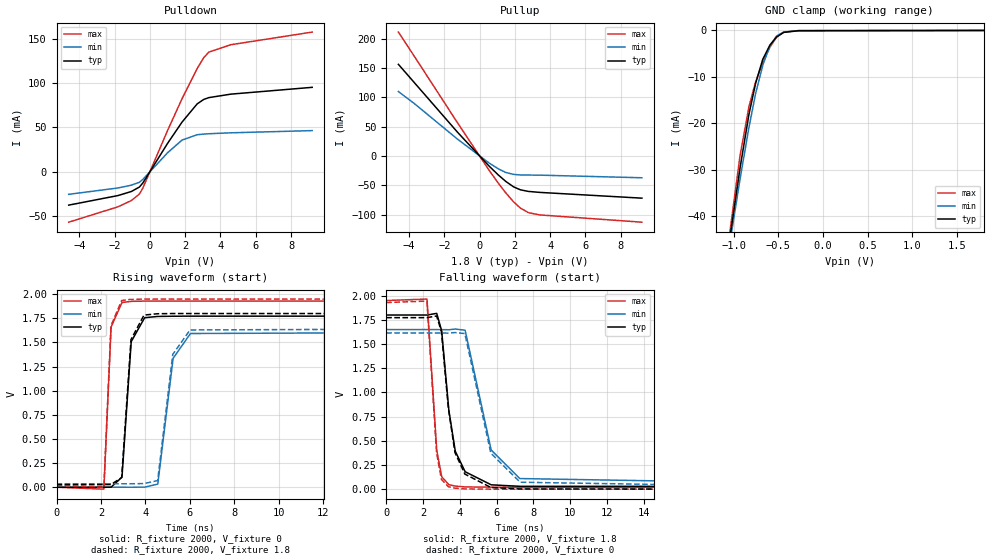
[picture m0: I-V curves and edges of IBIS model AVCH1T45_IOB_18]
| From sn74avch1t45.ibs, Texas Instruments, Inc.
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[Model]   AVCH1T45_IOB_18
Model_type  I/O
Vinl=0.5775
Vinh=1.2675
Enable   Active-High
Vref =   0
Rref =   2000
Cref =   15p
Vmeas =   0.9
| variable   typ   min   max
C_comp   5.26pF   4.50pF   5.87pF
| C_pullup   4.78pF   3.53pF   6.89pF
| C_pulldown   4.68pF   4.09pF   5.05pF
| C_tri-state   5.26pF   4.50pF   5.87pF
[Temperature Range]   40   100   -40
| Ambient temperature   25   85   -40
[Voltage range]   1.8   1.65   1.95
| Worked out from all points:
|   slope of the pulldown table from 0 to 0.27 V, typ, clamps not added: 30.8 ohm
|   slope of the pullup table from 0 to 0.27 V, typ, clamps not added: 31.4 ohm
|   GND clamp passes 1 mA (typ) near -0.49 V on its own axis
|   rising waveform, R_fixture 2000, V_fixture 0: 20-80 % time 290ps typ, 449ps min, 186ps max; typ from 0 V to 1.77 V
|   falling waveform, R_fixture 2000, V_fixture 1.8: 20-80 % time 652ps typ, 999ps min, 373ps max; typ from 1.8 V to 0.027 V
|   rising waveform, R_fixture 2000, V_fixture 1.8: 20-80 % time 288ps typ, 441ps min, 184ps max; typ from 0.027 V to 1.8 V
|   falling waveform, R_fixture 2000, V_fixture 0: 20-80 % time 653ps typ, 998ps min, 361ps max; typ from 1.77 V to 0 V
[GND Clamp]
| AVCH1T45_IOB_18
|   Voltage   I(typ)   I(min)   I(max)
-4.6V     -599.6mA   -548.2mA   -664.6mA
-1.1V     -52.38mA   -52.81mA   -51.88mA
-1.075V   -48.92mA   -49.68mA   -47.98mA
-930mV    -29.69mA   -32.08mA   -27.04mA
-830mV    -18.1mA    -20.91mA   -16.44mA
-755mV    -11.37mA   -13.59mA   -11.08mA
-675mV    -6.227mA   -7.502mA   -6.966mA
-595mV    -3.153mA   -3.319mA   -3.603mA
-520mV    -1.409mA   -1.191mA   -1.426mA
-440mV    -417.5uA   -333.3uA   -376.2uA
-275mV    -54.37uA   -36.84uA   -89.06uA
1.8V      918.7pA    21.47uA    -48.34uA
[Pulldown]
| AVCH1T45_IOB_18
|   Voltage   I(typ)   I(min)   I(max)
-4.6V     -37.94mA   -25.73mA   -57.23mA
-1.8V     -27.09mA   -18.52mA   -39.79mA
-1.045V   -22.5mA    -15.36mA   -32.7mA
-590mV    -17.44mA   -12.06mA   -25.35mA
-395mV    -12.81mA   -8.801mA   -18.52mA
1.005V    31.93mA    21.31mA    46.48mA
1.825V    55.97mA    35.61mA    82.46mA
2.68V     76.51mA    41.68mA    116.5mA
3.05V     81.53mA    42.39mA    128.7mA
3.34V     83.6mA     42.77mA    135mA
4.585V    87.54mA    43.82mA    143.4mA
9.2V      95.24mA    46.32mA    157.7mA
[Pullup]
| AVCH1T45_IOB_18
|   Voltage   I(typ)   I(min)   I(max)
-4.6V     156.3mA    109.9mA    211.2mA
-3.695V   125.1mA    89.45mA    169.9mA
-1.245V   40.55mA    28.8mA     56.51mA
535mV     -16.77mA   -11.6mA    -23.84mA
1.065V    -32.16mA   -21.66mA   -46.14mA
1.49V     -43.16mA   -27.88mA   -62.67mA
1.925V    -52.28mA   -31.05mA   -77.72mA
2.305V    -57.27mA   -32.09mA   -88.3mA
2.77V     -60.1mA    -32.26mA   -96.25mA
3.4V      -61.74mA   -32.39mA   -100.1mA
9.2V      -71.58mA   -36.85mA   -112.5mA
[Ramp]
| AVCH1T45_IOB_18
| variable   typ   min   max
dV/dt_r   1.08/3.02E-10   0.99/4.61E-10   1.17/1.95E-10
dV/dt_f   1.07/6.57E-10   0.98/1.01E-09   1.17/3.78E-10
R_load = 2000
[Rising Waveform]
| AVCH1T45_IOB_18
R_fixture =   2000
C_fixture =   0
L_fixture =   0
V_fixture =   0
V_fixture_min = 0
V_fixture_max = 0
|   Time   V(typ)   V(min)   V(max)
0s        21.35nV    98.25nV    665.6pV
2.13ns    39.05uV    -110.4nV   -20.1mV
2.455ns   604.2uV    -20.5uV    1.66V
2.945ns   104.5mV    15.93uV    1.914V
3.36ns    1.509V     -172.9uV   1.926V
3.965ns   1.757V     999.3uV    1.929V
4.555ns   1.77V      32.27mV    1.929V
5.245ns   1.772V     1.336V     1.929V
6.025ns   1.773V     1.593V     1.929V
29.99ns   1.773V     1.615V     1.929V
[Falling Waveform]
| AVCH1T45_IOB_18
R_fixture =   2000
C_fixture =   0
L_fixture =   0
V_fixture =   1.8
V_fixture_min = 1.65
V_fixture_max = 1.95
|   Time   V(typ)   V(min)   V(max)
0s        1.8V       1.65V      1.95V
2.215ns   1.8V       1.65V      1.965V
2.745ns   1.817V     1.65V      405.1mV
3.015ns   1.636V     1.649V     129mV
3.405ns   814.9mV    1.648V     46.72mV
3.755ns   392.1mV    1.655V     32.04mV
4.29ns    180.1mV    1.643V     23.24mV
5.705ns   44.96mV    405.1mV    20.42mV
7.26ns    29.59mV    109.7mV    20.34mV
29.99ns   27.01mV    36.05mV    20.32mV
[Rising Waveform]
| AVCH1T45_IOB_18
R_fixture =   2000
C_fixture =   0
L_fixture =   0
V_fixture =   1.8
V_fixture_min = 1.65
V_fixture_max = 1.95
|   Time   V(typ)   V(min)   V(max)
0s        27.01mV    36.05mV    20.32mV
2.13ns    27.05mV    36.05mV    495uV
2.45ns    27.53mV    36.03mV    1.673V
2.93ns    100.5mV    36.07mV    1.935V
3.35ns    1.53V      35.88mV    1.947V
3.935ns   1.784V     37.89mV    1.95V
4.55ns    1.798V     68.99mV    1.95V
5.23ns    1.8V       1.377V     1.95V
6.005ns   1.8V       1.63V      1.95V
29.99ns   1.8V       1.65V      1.95V
[Falling Waveform]
| AVCH1T45_IOB_18
R_fixture =   2000
C_fixture =   0
L_fixture =   0
V_fixture =   0
V_fixture_min = 0
V_fixture_max = 0
|   Time   V(typ)   V(min)   V(max)
0s        1.773V     1.615V     1.929V
2.215ns   1.773V     1.615V     1.944V
2.74ns    1.79V      1.615V     371.5mV
3ns       1.629V     1.614V     102mV
3.375ns   842.1mV    1.613V     26.04mV
3.735ns   379.7mV    1.619V     10.93mV
4.275ns   156mV      1.608V     2.612mV
5.69ns    17.29mV    370.9mV    85.87uV
7.28ns    2.194mV    71.85mV    11.35uV
29.99ns   89.43nV    1.385uV    172.5nV
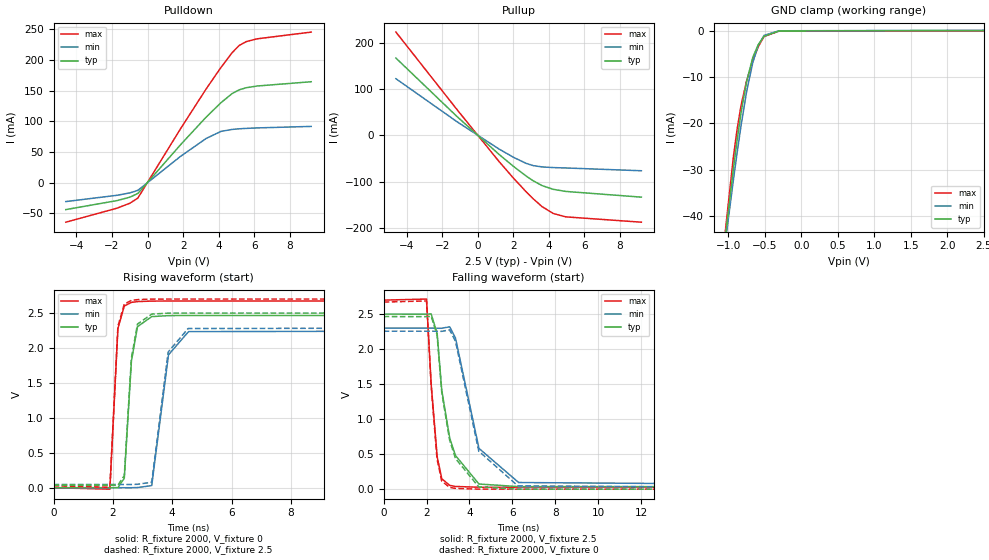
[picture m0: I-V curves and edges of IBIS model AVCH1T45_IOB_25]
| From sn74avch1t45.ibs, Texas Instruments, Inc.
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[Model]   AVCH1T45_IOB_25
Model_type  I/O
Vinl=0.7
Vinh=1.6
Enable   Active-High
Vref =   0
Rref =   2000
Cref =   15p
Vmeas =   1.25
| variable   typ   min   max
C_comp   5.06pF   4.25pF   5.75pF
| C_pullup   4.25pF   3.21pF   5.63pF
| C_pulldown   4.37pF   3.82pF   4.80pF
| C_tri-state   5.06pF   4.25pF   5.75pF
[Temperature Range]   40   100   -40
| Ambient temperature   25   85   -40
[Voltage range]   2.5   2.3   2.7
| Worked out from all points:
|   slope of the pulldown table from 0 to 0.375 V, typ, clamps not added: 29.4 ohm
|   slope of the pullup table from 0 to 0.375 V, typ, clamps not added: 28.8 ohm
|   GND clamp passes 1 mA (typ) near -0.49 V on its own axis
|   rising waveform, R_fixture 2000, V_fixture 0: 20-80 % time 216ps typ, 348ps min, 156ps max; typ from 0 V to 2.46 V
|   falling waveform, R_fixture 2000, V_fixture 2.5: 20-80 % time 733ps typ, 1.05ns min, 340ps max; typ from 2.5 V to 0.036 V
|   rising waveform, R_fixture 2000, V_fixture 2.5: 20-80 % time 214ps typ, 345ps min, 155ps max; typ from 0.036 V to 2.5 V
|   falling waveform, R_fixture 2000, V_fixture 0: 20-80 % time 728ps typ, 1.05ns min, 333ps max; typ from 2.46 V to 0 V
[GND Clamp]
| AVCH1T45_IOB_25
|   Voltage   I(typ)   I(min)   I(max)
-4.6V     -599.7mA   -548.2mA   -664.8mA
-1.105V   -53.1mA    -53.46mA   -52.72mA
-1.08V    -49.64mA   -50.32mA   -48.82mA
-930mV    -29.72mA   -32.1mA    -27.1mA
-880mV    -23.65mA   -26.37mA   -21.29mA
-825mV    -17.62mA   -20.4mA    -16.07mA
-750mV    -11.02mA   -13.17mA   -10.85mA
-665mV    -5.769mA   -6.898mA   -6.554mA
-590mV    -3.043mA   -3.142mA   -3.475mA
-510mV    -1.266mA   -1.045mA   -1.273mA
-305mV    -86.62uA   -60.85uA   -133.1uA
2.5V      1.212nA    39.39uA    -82.83uA
[Pulldown]
| AVCH1T45_IOB_25
|   Voltage   I(typ)   I(min)   I(max)
-4.6V     -43.76mA   -30.71mA   -64.27mA
-1.715V   -29.08mA   -20.46mA   -41.45mA
-985mV    -23.44mA   -16.53mA   -33.24mA
-545mV    -17.41mA   -12.35mA   -24.86mA
1.85V     61.76mA    42.85mA    87.78mA
3.295V    106.9mA    72.08mA    152.8mA
4.12V     130.1mA    83.49mA    187.5mA
4.755V    145.2mA    86.77mA    211.8mA
5.15V     151.2mA    87.75mA    223.4mA
5.545V    154.6mA    88.42mA    229.7mA
6.15V     157.4mA    89.19mA    234.2mA
9.2V      164.4mA    91.67mA    245.2mA
[Pullup]
| AVCH1T45_IOB_25
|   Voltage   I(typ)   I(min)   I(max)
-4.6V     167.2mA    122.6mA    223.3mA
-1.155V   40.55mA    29.45mA    55.44mA
1.195V    -40.71mA   -29.18mA   -56.05mA
2.025V    -67.14mA   -47.36mA   -92.77mA
2.695V    -86.73mA   -59.71mA   -120.4mA
3.12V     -97.9mA    -65.07mA   -136.7mA
3.615V    -108.1mA   -67.81mA   -153.5mA
4.245V    -116.2mA   -69.29mA   -168.4mA
4.95V     -120.8mA   -70.1mA    -175.7mA
9.2V      -133.1mA   -76.13mA   -187.2mA
[Ramp]
| AVCH1T45_IOB_25
| variable   typ   min   max
dV/dt_r   1.50/2.21E-10   1.38/3.60E-10   1.62/1.57E-10
dV/dt_f   1.49/7.36E-10   1.36/1.05E-09   1.62/3.43E-10
R_load = 2000
[Rising Waveform]
| AVCH1T45_IOB_25
R_fixture =   2000
C_fixture =   0
L_fixture =   0
V_fixture =   0
V_fixture_min = 0
V_fixture_max = 0
|   Time   V(typ)   V(min)   V(max)
0s        27.66nV    106.2nV    1.086nV
1.9ns     24.74uV    -1.293uV   -20.7mV
2.17ns    952.5uV    -25.5uV    2.278V
2.385ns   135.6mV    35.39uV    2.6V
2.625ns   1.81V      -211.2uV   2.653V
2.83ns    2.305V     2.727mV    2.664V
3.31ns    2.449V     30.4mV     2.671V
3.875ns   2.463V     1.902V     2.672V
4.55ns    2.465V     2.234V     2.672V
29.99ns   2.465V     2.256V     2.672V
[Falling Waveform]
| AVCH1T45_IOB_25
R_fixture =   2000
C_fixture =   0
L_fixture =   0
V_fixture =   2.5
V_fixture_min = 2.3
V_fixture_max = 2.7
|   Time   V(typ)   V(min)   V(max)
0s        2.5V       2.3V       2.7V
2ns       2.499V     2.3V       2.715V
2.215ns   2.503V     2.3V       1.506V
2.495ns   2.224V     2.298V     465.5mV
2.71ns    1.411V     2.298V     148.6mV
3.08ns    731.1mV    2.319V     54.35mV
3.35ns    480.5mV    2.158V     38.52mV
4.445ns   73.4mV     582.5mV    27.79mV
6.295ns   36.52mV    94.71mV    27.4mV
29.99ns   35.81mV    46.58mV    27.39mV
[Rising Waveform]
| AVCH1T45_IOB_25
R_fixture =   2000
C_fixture =   0
L_fixture =   0
V_fixture =   2.5
V_fixture_min = 2.3
V_fixture_max = 2.7
|   Time   V(typ)   V(min)   V(max)
0s        35.81mV    46.58mV    27.38mV
1.9ns     35.84mV    46.58mV    6.706mV
2.17ns    36.75mV    46.56mV    2.31V
2.385ns   172.9mV    46.62mV    2.628V
2.625ns   1.855V     46.37mV    2.681V
2.83ns    2.343V     49.31mV    2.692V
3.31ns    2.485V     78.63mV    2.699V
3.865ns   2.498V     1.943V     2.7V
4.535ns   2.5V       2.278V     2.7V
29.99ns   2.5V       2.3V       2.7V
[Falling Waveform]
| AVCH1T45_IOB_25
R_fixture =   2000
C_fixture =   0
L_fixture =   0
V_fixture =   0
V_fixture_min = 0
V_fixture_max = 0
|   Time   V(typ)   V(min)   V(max)
0s        2.465V     2.256V     2.672V
2ns       2.464V     2.256V     2.688V
2.215ns   2.468V     2.256V     1.48V
2.49ns    2.205V     2.255V     429.8mV
2.71ns    1.38V      2.254V     113.8mV
3.075ns   701.8mV    2.275V     25.9mV
3.35ns    437.7mV    2.112V     10.44mV
4.435ns   32.17mV    542.8mV    382.7uV
6.26ns    606.1uV    47.03mV    15.04uV
29.99ns   422nV      402.9nV    249.3nV
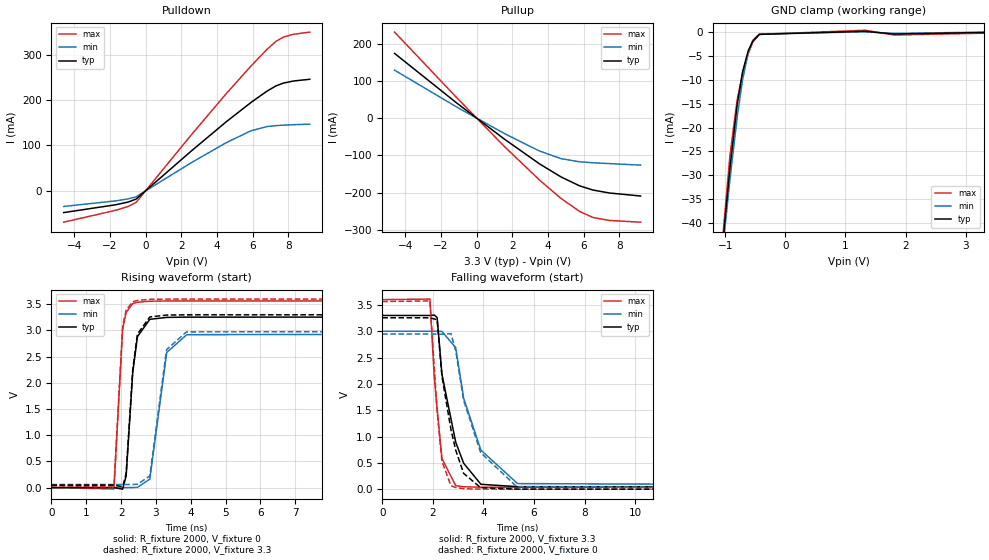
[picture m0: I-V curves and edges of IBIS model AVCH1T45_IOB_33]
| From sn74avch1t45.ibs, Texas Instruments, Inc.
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[Model]   AVCH1T45_IOB_33
Model_type  I/O
Vinl=0.8
Vinh=2.0
Enable   Active-High
Vref =   0
Rref =   2000
Cref =   15p
Vmeas =   1.65
| variable   typ   min   max
C_comp   4.94pF   3.95pF   5.92pF
| C_pullup   3.99pF   3.00pF   5.23pF
| C_pulldown   4.19pF   3.63pF   4.72pF
| C_tri-state   4.94pF   3.95pF   5.92pF
[Temperature Range]   40   100   -40
| Ambient temperature   25   85   -40
[Voltage range]   3.3   3   3.6
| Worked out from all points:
|   slope of the pulldown table from 0 to 0.495 V, typ, clamps not added: 28.7 ohm
|   slope of the pullup table from 0 to 0.495 V, typ, clamps not added: 27.4 ohm
|   GND clamp passes 1 mA (typ) near -0.49 V on its own axis
|   rising waveform, R_fixture 2000, V_fixture 0: 20-80 % time 203ps typ, 310ps min, 144ps max; typ from 0 V to 3.26 V
|   falling waveform, R_fixture 2000, V_fixture 3.3: 20-80 % time 750ps typ, 1.01ns min, 330ps max; typ from 3.3 V to 0.046 V
|   rising waveform, R_fixture 2000, V_fixture 3.3: 20-80 % time 202ps typ, 308ps min, 142ps max; typ from 0.046 V to 3.3 V
|   falling waveform, R_fixture 2000, V_fixture 0: 20-80 % time 667ps typ, 1.01ns min, 326ps max; typ from 3.26 V to 0 V
[GND Clamp]
| AVCH1T45_IOB_33
|   Voltage   I(typ)   I(min)   I(max)
-4.6V     -599.7mA   -548.3mA   -664.9mA
-1.12V    -55.23mA   -55.37mA   -55.14mA
-1.09V    -51.05mA   -51.59mA   -50.43mA
-920mV    -28.51mA   -30.95mA   -25.9mA
-800mV    -15.23mA   -17.87mA   -14.13mA
-710mV    -8.287mA   -9.958mA   -8.772mA
-615mV    -3.828mA   -4.226mA   -4.458mA
-540mV    -1.856mA   -1.633mA   -1.986mA
-430mV    -403.7uA   -315.6uA   -401.2uA
1.325V    252.6uA    143.2uA    467.7uA
1.81V     -334.6uA   -204.5uA   -541uA
3.3V      1.645nA    73.67uA    -145.7uA
[Pulldown]
| AVCH1T45_IOB_33
|   Voltage   I(typ)   I(min)   I(max)
-4.6V     -47.48mA   -33.99mA   -68.59mA
-1.68V    -30.25mA   -21.7mA    -42.42mA
-975mV    -24.15mA   -17.32mA   -33.81mA
-545mV    -17.86mA   -12.84mA   -25.24mA
2.535V    87.18mA    61.73mA    122.4mA
4.495V    151.5mA    105.8mA    213.1mA
5.9V      194.5mA    132.3mA    274.6mA
6.8V      219.5mA    141.6mA    311.3mA
7.31V     231.1mA    143.7mA    329.1mA
7.725V    237.2mA    144.7mA    338.4mA
8.275V    241.7mA    145.7mA    344.4mA
9.2V      245.6mA    146.9mA    349.3mA
[Pullup]
| AVCH1T45_IOB_33
|   Voltage   I(typ)   I(min)   I(max)
-4.6V     174.2mA    129.1mA    231.4mA
-1.105V   40.58mA    29.86mA    54.82mA
1.575V    -56.66mA   -41.45mA   -76.65mA
3.53V     -122.6mA   -88.07mA   -166.1mA
4.725V    -157.4mA   -108.5mA   -215.1mA
5.775V    -181.6mA   -117mA     -250.3mA
6.525V    -192.9mA   -119.7mA   -266.7mA
7.455V    -200.9mA   -121.9mA   -274.6mA
9.2V      -209mA     -126mA     -279.3mA
[Ramp]
| AVCH1T45_IOB_33
| variable   typ   min   max
dV/dt_r   1.98/2.08E-10   1.79/3.16E-10   2.16/1.47E-10
dV/dt_f   1.97/7.50E-10   1.78/1.01E-09   2.15/3.31E-10
R_load = 2000
[Rising Waveform]
| AVCH1T45_IOB_33
R_fixture =   2000
C_fixture =   0
L_fixture =   0
V_fixture =   0
V_fixture_min = 0
V_fixture_max = 0
|   Time   V(typ)   V(min)   V(max)
0s        37.78nV    120nV      1.948nV
1.795ns   -41.6uV    -5.552uV   -26.42mV
2.045ns   -30.58mV   27.81uV    3.027V
2.145ns   220.2mV    27.56uV    3.348V
2.335ns   2.2V       143.2uV    3.513V
2.47ns    2.882V     3.947mV    3.539V
2.825ns   3.213V     161mV      3.559V
3.31ns    3.25V      2.579V     3.564V
3.885ns   3.255V     2.92V      3.564V
29.99ns   3.256V     2.946V     3.564V
[Falling Waveform]
| AVCH1T45_IOB_33
R_fixture =   2000
C_fixture =   0
L_fixture =   0
V_fixture =   3.3
V_fixture_min = 3
V_fixture_max = 3.6
|   Time   V(typ)   V(min)   V(max)
0s        3.3V       3V         3.6V
1.885ns   3.299V     3V         3.611V
2.055ns   3.308V     3V         2.144V
2.17ns    3.261V     2.999V     1.523V
2.36ns    2.183V     2.996V     583mV
2.905ns   891.3mV    2.687V     66.55mV
3.22ns    491.5mV    1.726V     45.56mV
3.9ns     92.52mV    741.9mV    36.96mV
5.35ns    47.14mV    105.8mV    35.99mV
29.99ns   46.09mV    58.43mV    35.95mV
[Rising Waveform]
| AVCH1T45_IOB_33
R_fixture =   2000
C_fixture =   0
L_fixture =   0
V_fixture =   3.3
V_fixture_min = 3
V_fixture_max = 3.6
|   Time   V(typ)   V(min)   V(max)
0s        46.09mV    58.43mV    35.95mV
1.795ns   46.05mV    58.42mV    9.442mV
2.045ns   15.39mV    58.46mV    3.075V
2.145ns   267.5mV    58.46mV    3.39V
2.335ns   2.253V     58.57mV    3.549V
2.47ns    2.932V     62.39mV    3.575V
2.825ns   3.258V     221.7mV    3.595V
3.305ns   3.294V     2.633V     3.599V
3.875ns   3.299V     2.973V     3.6V
29.99ns   3.3V       3V         3.6V
[Falling Waveform]
| AVCH1T45_IOB_33
R_fixture =   2000
C_fixture =   0
L_fixture =   0
V_fixture =   0
V_fixture_min = 0
V_fixture_max = 0
|   Time   V(typ)   V(min)   V(max)
0s        3.256V     2.946V     3.564V
1.885ns   3.255V     2.946V     3.576V
2.17ns    3.218V     2.945V     1.481V
2.36ns    2.144V     2.942V     529.6mV
2.715ns   1.136V     2.955V     65.01mV
2.905ns   741.1mV    2.632V     29.77mV
3.215ns   300.7mV    1.691V     9.446mV
3.89ns    28.49mV    694.6mV    1.001mV
5.315ns   658.2uV    47.79mV    36.34uV
29.99ns   549.6nV    809.6nV    241.2nV
